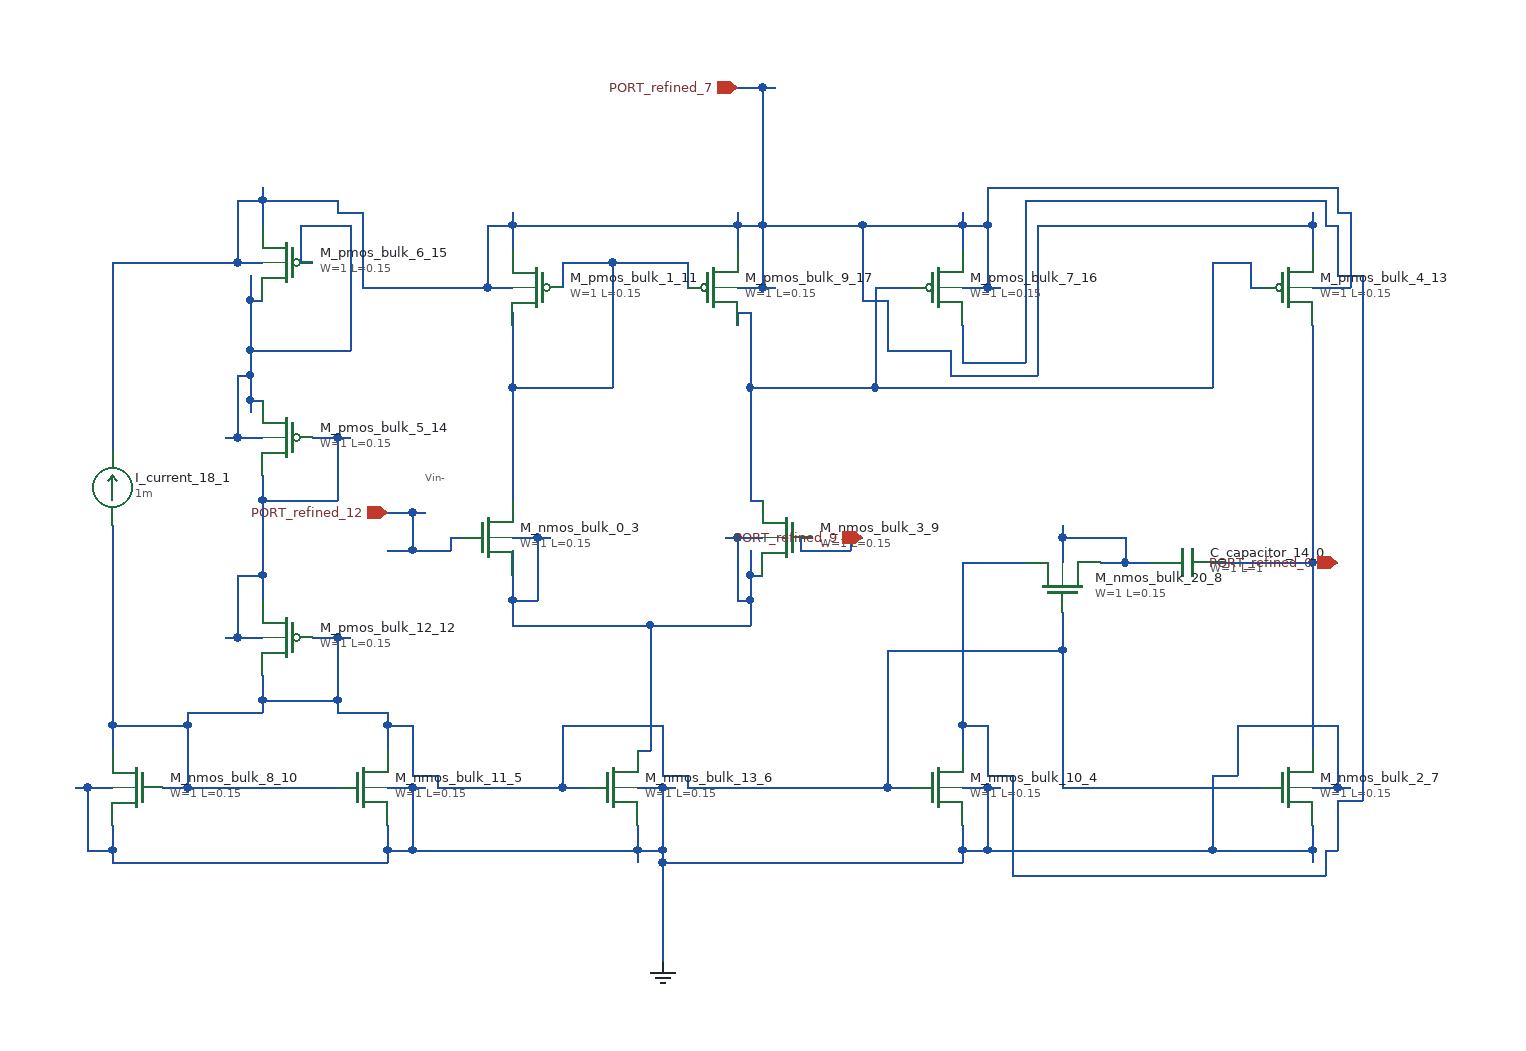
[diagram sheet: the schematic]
v {xschem version=3.4.8 file_version=1.2}
G {}
K {}
V {}
S {}
E {}
C {sky130_fd_pr/cap_mim_m3_1.sym} 980 420 3 0 {name="C_capacitor_14_0" model=cap_mim_m3_1 W=1 L=1 MF=1 spiceprefix=X}
C {devices/isource.sym} 120 360 2 0 {name="I_current_18_1" value=1m}
C {devices/gnd.sym} 560 740 0 0 {name="l_gnd_15_2" lab="GND"}
C {sky130_fd_pr/nfet_01v8.sym} 420 400 0 0 {name="M_nmos_bulk_0_3"
W=1
L=0.15
nf=1 
mult=1
ad="expr('int((@nf + 1)/2) * @W / @nf * 0.29')"
pd="expr('2*int((@nf + 1)/2) * (@W / @nf + 0.29)')"
as="expr('int((@nf + 2)/2) * @W / @nf * 0.29')"
ps="expr('2*int((@nf + 2)/2) * (@W / @nf + 0.29)')"
nrd="expr('0.29 / @W ')" nrs="expr('0.29 / @W ')"
sa=0 sb=0 sd=0
model=nfet_01v8
spiceprefix=X
}
C {sky130_fd_pr/nfet_01v8.sym} 780 600 0 0 {name="M_nmos_bulk_10_4"
W=1
L=0.15
nf=1 
mult=1
ad="expr('int((@nf + 1)/2) * @W / @nf * 0.29')"
pd="expr('2*int((@nf + 1)/2) * (@W / @nf + 0.29)')"
as="expr('int((@nf + 2)/2) * @W / @nf * 0.29')"
ps="expr('2*int((@nf + 2)/2) * (@W / @nf + 0.29)')"
nrd="expr('0.29 / @W ')" nrs="expr('0.29 / @W ')"
sa=0 sb=0 sd=0
model=nfet_01v8
spiceprefix=X
}
C {sky130_fd_pr/nfet_01v8.sym} 320 600 0 0 {name="M_nmos_bulk_11_5"
W=1
L=0.15
nf=1 
mult=1
ad="expr('int((@nf + 1)/2) * @W / @nf * 0.29')"
pd="expr('2*int((@nf + 1)/2) * (@W / @nf + 0.29)')"
as="expr('int((@nf + 2)/2) * @W / @nf * 0.29')"
ps="expr('2*int((@nf + 2)/2) * (@W / @nf + 0.29)')"
nrd="expr('0.29 / @W ')" nrs="expr('0.29 / @W ')"
sa=0 sb=0 sd=0
model=nfet_01v8
spiceprefix=X
}
C {sky130_fd_pr/nfet_01v8.sym} 520 600 0 0 {name="M_nmos_bulk_13_6"
W=1
L=0.15
nf=1 
mult=1
ad="expr('int((@nf + 1)/2) * @W / @nf * 0.29')"
pd="expr('2*int((@nf + 1)/2) * (@W / @nf + 0.29)')"
as="expr('int((@nf + 2)/2) * @W / @nf * 0.29')"
ps="expr('2*int((@nf + 2)/2) * (@W / @nf + 0.29)')"
nrd="expr('0.29 / @W ')" nrs="expr('0.29 / @W ')"
sa=0 sb=0 sd=0
model=nfet_01v8
spiceprefix=X
}
C {sky130_fd_pr/nfet_01v8.sym} 1060 600 0 0 {name="M_nmos_bulk_2_7"
W=1
L=0.15
nf=1 
mult=1
ad="expr('int((@nf + 1)/2) * @W / @nf * 0.29')"
pd="expr('2*int((@nf + 1)/2) * (@W / @nf + 0.29)')"
as="expr('int((@nf + 2)/2) * @W / @nf * 0.29')"
ps="expr('2*int((@nf + 2)/2) * (@W / @nf + 0.29)')"
nrd="expr('0.29 / @W ')" nrs="expr('0.29 / @W ')"
sa=0 sb=0 sd=0
model=nfet_01v8
spiceprefix=X
}
C {sky130_fd_pr/nfet_01v8.sym} 880 440 3 0 {name="M_nmos_bulk_20_8"
W=1
L=0.15
nf=1 
mult=1
ad="expr('int((@nf + 1)/2) * @W / @nf * 0.29')"
pd="expr('2*int((@nf + 1)/2) * (@W / @nf + 0.29)')"
as="expr('int((@nf + 2)/2) * @W / @nf * 0.29')"
ps="expr('2*int((@nf + 2)/2) * (@W / @nf + 0.29)')"
nrd="expr('0.29 / @W ')" nrs="expr('0.29 / @W ')"
sa=0 sb=0 sd=0
model=nfet_01v8
spiceprefix=X
}
C {sky130_fd_pr/nfet_01v8.sym} 660 400 0 1 {name="M_nmos_bulk_3_9"
W=1
L=0.15
nf=1 
mult=1
ad="expr('int((@nf + 1)/2) * @W / @nf * 0.29')"
pd="expr('2*int((@nf + 1)/2) * (@W / @nf + 0.29)')"
as="expr('int((@nf + 2)/2) * @W / @nf * 0.29')"
ps="expr('2*int((@nf + 2)/2) * (@W / @nf + 0.29)')"
nrd="expr('0.29 / @W ')" nrs="expr('0.29 / @W ')"
sa=0 sb=0 sd=0
model=nfet_01v8
spiceprefix=X
}
C {sky130_fd_pr/nfet_01v8.sym} 140 600 0 1 {name="M_nmos_bulk_8_10"
W=1
L=0.15
nf=1 
mult=1
ad="expr('int((@nf + 1)/2) * @W / @nf * 0.29')"
pd="expr('2*int((@nf + 1)/2) * (@W / @nf + 0.29)')"
as="expr('int((@nf + 2)/2) * @W / @nf * 0.29')"
ps="expr('2*int((@nf + 2)/2) * (@W / @nf + 0.29)')"
nrd="expr('0.29 / @W ')" nrs="expr('0.29 / @W ')"
sa=0 sb=0 sd=0
model=nfet_01v8
spiceprefix=X
}
C {sky130_fd_pr/pfet_01v8.sym} 460 200 0 1 {name="M_pmos_bulk_1_11"
W=1
L=0.15
nf=1
mult=1
ad="expr('int((@nf + 1)/2) * @W / @nf * 0.29')"
pd="expr('2*int((@nf + 1)/2) * (@W / @nf + 0.29)')"
as="expr('int((@nf + 2)/2) * @W / @nf * 0.29')"
ps="expr('2*int((@nf + 2)/2) * (@W / @nf + 0.29)')"
nrd="expr('0.29 / @W ')" nrs="expr('0.29 / @W ')"
sa=0 sb=0 sd=0
model=pfet_01v8
spiceprefix=X
}
C {sky130_fd_pr/pfet_01v8.sym} 260 480 0 1 {name="M_pmos_bulk_12_12"
W=1
L=0.15
nf=1
mult=1
ad="expr('int((@nf + 1)/2) * @W / @nf * 0.29')"
pd="expr('2*int((@nf + 1)/2) * (@W / @nf + 0.29)')"
as="expr('int((@nf + 2)/2) * @W / @nf * 0.29')"
ps="expr('2*int((@nf + 2)/2) * (@W / @nf + 0.29)')"
nrd="expr('0.29 / @W ')" nrs="expr('0.29 / @W ')"
sa=0 sb=0 sd=0
model=pfet_01v8
spiceprefix=X
}
C {sky130_fd_pr/pfet_01v8.sym} 1060 200 0 0 {name="M_pmos_bulk_4_13"
W=1
L=0.15
nf=1
mult=1
ad="expr('int((@nf + 1)/2) * @W / @nf * 0.29')"
pd="expr('2*int((@nf + 1)/2) * (@W / @nf + 0.29)')"
as="expr('int((@nf + 2)/2) * @W / @nf * 0.29')"
ps="expr('2*int((@nf + 2)/2) * (@W / @nf + 0.29)')"
nrd="expr('0.29 / @W ')" nrs="expr('0.29 / @W ')"
sa=0 sb=0 sd=0
model=pfet_01v8
spiceprefix=X
}
C {sky130_fd_pr/pfet_01v8.sym} 260 320 0 1 {name="M_pmos_bulk_5_14"
W=1
L=0.15
nf=1
mult=1
ad="expr('int((@nf + 1)/2) * @W / @nf * 0.29')"
pd="expr('2*int((@nf + 1)/2) * (@W / @nf + 0.29)')"
as="expr('int((@nf + 2)/2) * @W / @nf * 0.29')"
ps="expr('2*int((@nf + 2)/2) * (@W / @nf + 0.29)')"
nrd="expr('0.29 / @W ')" nrs="expr('0.29 / @W ')"
sa=0 sb=0 sd=0
model=pfet_01v8
spiceprefix=X
}
C {sky130_fd_pr/pfet_01v8.sym} 260 180 0 1 {name="M_pmos_bulk_6_15"
W=1
L=0.15
nf=1
mult=1
ad="expr('int((@nf + 1)/2) * @W / @nf * 0.29')"
pd="expr('2*int((@nf + 1)/2) * (@W / @nf + 0.29)')"
as="expr('int((@nf + 2)/2) * @W / @nf * 0.29')"
ps="expr('2*int((@nf + 2)/2) * (@W / @nf + 0.29)')"
nrd="expr('0.29 / @W ')" nrs="expr('0.29 / @W ')"
sa=0 sb=0 sd=0
model=pfet_01v8
spiceprefix=X
}
C {sky130_fd_pr/pfet_01v8.sym} 780 200 0 0 {name="M_pmos_bulk_7_16"
W=1
L=0.15
nf=1
mult=1
ad="expr('int((@nf + 1)/2) * @W / @nf * 0.29')"
pd="expr('2*int((@nf + 1)/2) * (@W / @nf + 0.29)')"
as="expr('int((@nf + 2)/2) * @W / @nf * 0.29')"
ps="expr('2*int((@nf + 2)/2) * (@W / @nf + 0.29)')"
nrd="expr('0.29 / @W ')" nrs="expr('0.29 / @W ')"
sa=0 sb=0 sd=0
model=pfet_01v8
spiceprefix=X
}
C {sky130_fd_pr/pfet_01v8.sym} 600 200 0 0 {name="M_pmos_bulk_9_17"
W=1
L=0.15
nf=1
mult=1
ad="expr('int((@nf + 1)/2) * @W / @nf * 0.29')"
pd="expr('2*int((@nf + 1)/2) * (@W / @nf + 0.29)')"
as="expr('int((@nf + 2)/2) * @W / @nf * 0.29')"
ps="expr('2*int((@nf + 2)/2) * (@W / @nf + 0.29)')"
nrd="expr('0.29 / @W ')" nrs="expr('0.29 / @W ')"
sa=0 sb=0 sd=0
model=pfet_01v8
spiceprefix=X
}
C {devices/ipin.sym} 1100 420 0 0 {name="p_port_16_18" lab="PORT_refined_0"}
C {devices/ipin.sym} 620 40 0 0 {name="p_port_17_19" lab="PORT_refined_7"}
C {devices/ipin.sym} 720 400 0 0 {name="p_port_21_20" lab="PORT_refined_9"}
C {devices/ipin.sym} 340 380 0 0 {name="p_port_22_21" lab="PORT_refined_12"}
T {Vin-} 370 340 0 0 0.25 0.25 {}
N 1000 420 1010 420 {}
N 1010 420 1080 420 {}
N 1080 420 1100 420 {}
N 1080 570 1080 420 {}
N 1080 420 1080 230 {}
N 910 420 930 420 {}
N 930 420 950 420 {}
N 950 420 970 420 {}
N 880 400 930 400 {}
N 880 420 880 400 {}
N 880 400 880 390 {}
N 930 420 930 400 {}
N 440 280 520 280 {}
N 480 180 520 180 {}
N 520 180 580 180 {}
N 440 370 440 280 {}
N 440 280 440 230 {}
N 440 230 440 220 {}
N 480 200 480 180 {}
N 520 280 520 180 {}
N 580 200 580 180 {}
N 210 320 220 320 {}
N 220 320 240 320 {}
N 230 290 240 290 {}
N 220 270 230 270 {}
N 230 250 310 250 {}
N 230 210 240 210 {}
N 270 180 280 180 {}
N 270 150 310 150 {}
N 220 320 220 270 {}
N 230 300 230 290 {}
N 230 290 230 270 {}
N 230 270 230 250 {}
N 230 250 230 210 {}
N 230 210 230 190 {}
N 270 180 270 150 {}
N 310 250 310 150 {}
N 340 410 360 410 {}
N 360 410 390 410 {}
N 390 400 400 400 {}
N 340 380 360 380 {}
N 360 380 370 380 {}
N 360 410 360 380 {}
N 390 410 390 400 {}
N 840 670 1090 670 {}
N 1090 650 1100 650 {}
N 1100 610 1120 610 {}
N 820 590 840 590 {}
N 800 550 820 550 {}
N 800 420 850 420 {}
N 800 260 850 260 {}
N 1100 190 1120 190 {}
N 1090 150 1100 150 {}
N 850 130 1090 130 {}
N 800 570 800 550 {}
N 800 550 800 420 {}
N 800 260 800 230 {}
N 820 590 820 550 {}
N 840 670 840 590 {}
N 850 260 850 130 {}
N 1090 670 1090 650 {}
N 1090 150 1090 130 {}
N 1100 650 1100 610 {}
N 1100 190 1100 150 {}
N 1120 610 1120 190 {}
N 120 660 340 660 {}
N 560 660 800 660 {}
N 100 650 120 650 {}
N 340 650 360 650 {}
N 360 650 540 650 {}
N 540 650 560 650 {}
N 800 650 820 650 {}
N 820 650 1000 650 {}
N 1000 650 1080 650 {}
N 90 600 100 600 {}
N 100 600 120 600 {}
N 340 600 360 600 {}
N 360 600 370 600 {}
N 540 600 560 600 {}
N 560 600 570 600 {}
N 800 600 820 600 {}
N 820 600 830 600 {}
N 1080 600 1100 600 {}
N 1100 600 1110 600 {}
N 1000 590 1020 590 {}
N 1020 550 1100 550 {}
N 100 650 100 600 {}
N 120 660 120 650 {}
N 120 650 120 630 {}
N 340 660 340 650 {}
N 340 650 340 630 {}
N 360 650 360 600 {}
N 540 660 540 650 {}
N 540 650 540 630 {}
N 560 740 560 660 {}
N 560 660 560 650 {}
N 560 650 560 600 {}
N 800 660 800 650 {}
N 800 650 800 630 {}
N 820 650 820 600 {}
N 1000 650 1000 590 {}
N 1020 590 1020 550 {}
N 1080 660 1080 650 {}
N 1080 650 1080 630 {}
N 1100 600 1100 550 {}
N 160 600 180 600 {}
N 180 600 300 600 {}
N 380 600 480 600 {}
N 480 600 500 600 {}
N 580 600 740 600 {}
N 740 600 760 600 {}
N 880 600 1040 600 {}
N 360 590 380 590 {}
N 560 590 580 590 {}
N 120 550 180 550 {}
N 340 550 360 550 {}
N 480 550 560 550 {}
N 180 540 240 540 {}
N 300 540 340 540 {}
N 240 530 300 530 {}
N 740 490 880 490 {}
N 280 480 300 480 {}
N 300 480 310 480 {}
N 120 570 120 550 {}
N 120 550 120 390 {}
N 180 600 180 550 {}
N 180 550 180 540 {}
N 240 540 240 530 {}
N 240 530 240 510 {}
N 300 540 300 530 {}
N 300 530 300 480 {}
N 340 570 340 550 {}
N 340 550 340 540 {}
N 360 590 360 550 {}
N 380 600 380 590 {}
N 480 600 480 550 {}
N 560 590 560 550 {}
N 580 600 580 590 {}
N 740 600 740 490 {}
N 880 600 880 490 {}
N 880 490 880 460 {}
N 540 570 550 570 {}
N 440 470 550 470 {}
N 550 470 630 470 {}
N 440 450 460 450 {}
N 620 450 630 450 {}
N 630 430 640 430 {}
N 440 400 460 400 {}
N 460 400 470 400 {}
N 610 400 620 400 {}
N 620 400 640 400 {}
N 440 470 440 450 {}
N 440 450 440 430 {}
N 440 430 440 410 {}
N 460 450 460 400 {}
N 550 570 550 470 {}
N 620 450 620 400 {}
N 630 470 630 450 {}
N 630 450 630 430 {}
N 630 430 630 410 {}
N 210 480 220 480 {}
N 220 480 240 480 {}
N 220 430 240 430 {}
N 240 370 300 370 {}
N 280 320 300 320 {}
N 300 320 310 320 {}
N 220 480 220 430 {}
N 240 450 240 430 {}
N 240 430 240 370 {}
N 240 370 240 350 {}
N 300 370 300 320 {}
N 790 270 860 270 {}
N 740 250 790 250 {}
N 720 210 740 210 {}
N 320 200 420 200 {}
N 420 200 440 200 {}
N 620 200 640 200 {}
N 640 200 650 200 {}
N 800 200 820 200 {}
N 820 200 830 200 {}
N 1080 200 1110 200 {}
N 120 180 220 180 {}
N 220 180 240 180 {}
N 420 150 440 150 {}
N 440 150 620 150 {}
N 620 150 640 150 {}
N 640 150 720 150 {}
N 720 150 800 150 {}
N 800 150 820 150 {}
N 860 150 1080 150 {}
N 300 140 320 140 {}
N 1100 140 1110 140 {}
N 220 130 240 130 {}
N 240 130 300 130 {}
N 820 120 1100 120 {}
N 620 40 640 40 {}
N 640 40 650 40 {}
N 120 330 120 180 {}
N 220 180 220 130 {}
N 240 150 240 130 {}
N 240 130 240 120 {}
N 300 140 300 130 {}
N 320 200 320 140 {}
N 420 200 420 150 {}
N 440 170 440 150 {}
N 440 150 440 140 {}
N 620 170 620 150 {}
N 620 150 620 140 {}
N 640 200 640 150 {}
N 640 150 640 40 {}
N 720 210 720 150 {}
N 740 250 740 210 {}
N 790 270 790 250 {}
N 800 170 800 150 {}
N 800 150 800 140 {}
N 820 200 820 150 {}
N 820 150 820 120 {}
N 860 270 860 150 {}
N 1080 170 1080 150 {}
N 1080 150 1080 140 {}
N 1100 140 1100 120 {}
N 1110 200 1110 140 {}
N 630 370 640 370 {}
N 630 280 730 280 {}
N 730 280 1000 280 {}
N 620 220 630 220 {}
N 730 200 760 200 {}
N 1030 200 1040 200 {}
N 1000 180 1030 180 {}
N 620 230 620 220 {}
N 630 370 630 280 {}
N 630 280 630 220 {}
N 730 280 730 200 {}
N 1000 280 1000 180 {}
N 1030 200 1030 180 {}
N 670 410 710 410 {}
N 670 400 680 400 {}
N 710 400 720 400 {}
N 670 410 670 400 {}
N 710 410 710 400 {}
